VERSION 5.7 ;
  NOWIREEXTENSIONATPIN ON ;
  DIVIDERCHAR "/" ;
  BUSBITCHARS "[]" ;
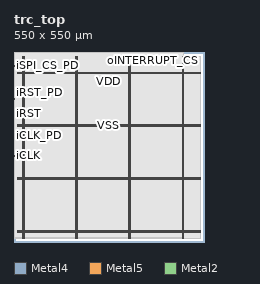
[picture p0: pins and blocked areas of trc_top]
MACRO trc_top
  CLASS BLOCK ;
  FOREIGN trc_top ;
  ORIGIN 0.000 0.000 ;
  SIZE 550.000 BY 550.000 ;
  PIN VDD
    DIRECTION INOUT ;
    USE POWER ;
    PORT
      LAYER Metal4 ;
        RECT 25.600 11.460 27.200 537.340 ;
    END
    PORT
      LAYER Metal4 ;
        RECT 179.200 11.460 180.800 537.340 ;
    END
    PORT
      LAYER Metal4 ;
        RECT 332.800 11.460 334.400 537.340 ;
    END
    PORT
      LAYER Metal4 ;
        RECT 486.400 11.460 488.000 537.340 ;
    END
    PORT
      LAYER Metal5 ;
        RECT 10.080 27.610 539.840 29.210 ;
    END
    PORT
      LAYER Metal5 ;
        RECT 10.080 180.790 539.840 182.390 ;
    END
    PORT
      LAYER Metal5 ;
        RECT 10.080 333.970 539.840 335.570 ;
    END
    PORT
      LAYER Metal5 ;
        RECT 10.080 487.150 539.840 488.750 ;
    END
  END VDD
  PIN VSS
    DIRECTION INOUT ;
    USE GROUND ;
    PORT
      LAYER Metal4 ;
        RECT 28.900 11.460 30.500 537.340 ;
    END
    PORT
      LAYER Metal4 ;
        RECT 182.500 11.460 184.100 537.340 ;
    END
    PORT
      LAYER Metal4 ;
        RECT 336.100 11.460 337.700 537.340 ;
    END
    PORT
      LAYER Metal4 ;
        RECT 489.700 11.460 491.300 537.340 ;
    END
    PORT
      LAYER Metal5 ;
        RECT 10.080 30.910 539.840 32.510 ;
    END
    PORT
      LAYER Metal5 ;
        RECT 10.080 184.090 539.840 185.690 ;
    END
    PORT
      LAYER Metal5 ;
        RECT 10.080 337.270 539.840 338.870 ;
    END
    PORT
      LAYER Metal5 ;
        RECT 10.080 490.450 539.840 492.050 ;
    END
  END VSS
  PIN iCLK
    DIRECTION INPUT ;
    USE SIGNAL ;
    ANTENNAGATEAREA 4.738000 ;
    PORT
      LAYER Metal2 ;
        RECT 0.000 248.760 1.000 249.140 ;
    END
  END iCLK
  PIN iCLK_PD
    DIRECTION OUTPUT ;
    USE SIGNAL ;
    ANTENNADIFFAREA 0.536800 ;
    PORT
      LAYER Metal2 ;
        RECT 0.000 309.290 1.000 309.670 ;
    END
  END iCLK_PD
  PIN iCLK_PU
    DIRECTION OUTPUT ;
    USE SIGNAL ;
    ANTENNADIFFAREA 0.360800 ;
    PORT
      LAYER Metal2 ;
        RECT 0.000 313.655 1.000 314.035 ;
    END
  END iCLK_PU
  PIN iRST
    DIRECTION INPUT ;
    USE SIGNAL ;
    ANTENNAGATEAREA 4.408000 ;
    PORT
      LAYER Metal2 ;
        RECT 0.000 348.760 1.000 349.140 ;
    END
  END iRST
  PIN iRST_PD
    DIRECTION OUTPUT ;
    USE SIGNAL ;
    ANTENNADIFFAREA 0.360800 ;
    PORT
      LAYER Metal2 ;
        RECT 0.000 409.290 1.000 409.670 ;
    END
  END iRST_PD
  PIN iRST_PU
    DIRECTION OUTPUT ;
    USE SIGNAL ;
    ANTENNADIFFAREA 0.536800 ;
    PORT
      LAYER Metal2 ;
        RECT 0.000 413.655 1.000 414.035 ;
    END
  END iRST_PU
  PIN iSPI_CS
    DIRECTION INPUT ;
    USE SIGNAL ;
    ANTENNAGATEAREA 0.498500 ;
    PORT
      LAYER Metal2 ;
        RECT 0.000 448.760 1.000 449.140 ;
    END
  END iSPI_CS
  PIN iSPI_CS_PD
    DIRECTION OUTPUT ;
    USE SIGNAL ;
    ANTENNADIFFAREA 0.360800 ;
    PORT
      LAYER Metal2 ;
        RECT 0.000 509.290 1.000 509.670 ;
    END
  END iSPI_CS_PD
  PIN iSPI_CS_PU
    DIRECTION OUTPUT ;
    USE SIGNAL ;
    ANTENNADIFFAREA 0.536800 ;
    PORT
      LAYER Metal2 ;
        RECT 0.000 513.655 1.000 514.035 ;
    END
  END iSPI_CS_PU
  PIN iSPI_MOSI
    DIRECTION INPUT ;
    USE SIGNAL ;
    ANTENNAGATEAREA 0.396000 ;
    PORT
      LAYER Metal2 ;
        RECT 133.760 549.000 134.140 550.000 ;
    END
  END iSPI_MOSI
  PIN iSPI_MOSI_PD
    DIRECTION OUTPUT ;
    USE SIGNAL ;
    ANTENNADIFFAREA 0.536800 ;
    PORT
      LAYER Metal2 ;
        RECT 194.290 549.000 194.670 550.000 ;
    END
  END iSPI_MOSI_PD
  PIN iSPI_MOSI_PU
    DIRECTION OUTPUT ;
    USE SIGNAL ;
    ANTENNADIFFAREA 0.360800 ;
    PORT
      LAYER Metal2 ;
        RECT 198.655 549.000 199.035 550.000 ;
    END
  END iSPI_MOSI_PU
  PIN iSPI_SCK
    DIRECTION INPUT ;
    USE SIGNAL ;
    ANTENNAGATEAREA 0.498500 ;
    PORT
      LAYER Metal2 ;
        RECT 33.760 549.000 34.140 550.000 ;
    END
  END iSPI_SCK
  PIN iSPI_SCK_PD
    DIRECTION OUTPUT ;
    USE SIGNAL ;
    ANTENNADIFFAREA 0.536800 ;
    PORT
      LAYER Metal2 ;
        RECT 94.290 549.000 94.670 550.000 ;
    END
  END iSPI_SCK_PD
  PIN iSPI_SCK_PU
    DIRECTION OUTPUT ;
    USE SIGNAL ;
    ANTENNADIFFAREA 0.360800 ;
    PORT
      LAYER Metal2 ;
        RECT 98.655 549.000 99.035 550.000 ;
    END
  END iSPI_SCK_PU
  PIN oINTERRUPT_CS
    DIRECTION OUTPUT ;
    USE SIGNAL ;
    ANTENNADIFFAREA 0.360800 ;
    PORT
      LAYER Metal2 ;
        RECT 401.260 549.000 401.640 550.000 ;
    END
  END oINTERRUPT_CS
  PIN oINTERRUPT_IE
    DIRECTION OUTPUT ;
    USE SIGNAL ;
    ANTENNADIFFAREA 0.360800 ;
    PORT
      LAYER Metal2 ;
        RECT 393.235 549.000 393.615 550.000 ;
    END
  END oINTERRUPT_IE
  PIN oINTERRUPT_IN
    DIRECTION INPUT ;
    USE SIGNAL ;
    PORT
      LAYER Metal2 ;
        RECT 333.760 549.000 334.140 550.000 ;
    END
  END oINTERRUPT_IN
  PIN oINTERRUPT_OE
    DIRECTION OUTPUT ;
    USE SIGNAL ;
    ANTENNADIFFAREA 0.536800 ;
    PORT
      LAYER Metal2 ;
        RECT 334.490 549.000 334.870 550.000 ;
    END
  END oINTERRUPT_OE
  PIN oINTERRUPT_OUT
    DIRECTION OUTPUT ;
    USE SIGNAL ;
    ANTENNADIFFAREA 1.986000 ;
    PORT
      LAYER Metal2 ;
        RECT 335.220 549.000 335.600 550.000 ;
    END
  END oINTERRUPT_OUT
  PIN oINTERRUPT_PD
    DIRECTION OUTPUT ;
    USE SIGNAL ;
    ANTENNADIFFAREA 0.360800 ;
    PORT
      LAYER Metal2 ;
        RECT 394.290 549.000 394.670 550.000 ;
    END
  END oINTERRUPT_PD
  PIN oINTERRUPT_PDRV0
    DIRECTION OUTPUT ;
    USE SIGNAL ;
    ANTENNADIFFAREA 0.536800 ;
    PORT
      LAYER Metal2 ;
        RECT 397.510 549.000 397.890 550.000 ;
    END
  END oINTERRUPT_PDRV0
  PIN oINTERRUPT_PDRV1
    DIRECTION OUTPUT ;
    USE SIGNAL ;
    ANTENNADIFFAREA 0.536800 ;
    PORT
      LAYER Metal2 ;
        RECT 396.800 549.000 397.180 550.000 ;
    END
  END oINTERRUPT_PDRV1
  PIN oINTERRUPT_PU
    DIRECTION OUTPUT ;
    USE SIGNAL ;
    ANTENNADIFFAREA 0.360800 ;
    PORT
      LAYER Metal2 ;
        RECT 398.655 549.000 399.035 550.000 ;
    END
  END oINTERRUPT_PU
  PIN oINTERRUPT_SL
    DIRECTION OUTPUT ;
    USE SIGNAL ;
    ANTENNADIFFAREA 0.360800 ;
    PORT
      LAYER Metal2 ;
        RECT 335.950 549.000 336.330 550.000 ;
    END
  END oINTERRUPT_SL
  PIN oSPI_MISO_CS
    DIRECTION OUTPUT ;
    USE SIGNAL ;
    ANTENNADIFFAREA 0.360800 ;
    PORT
      LAYER Metal2 ;
        RECT 301.260 549.000 301.640 550.000 ;
    END
  END oSPI_MISO_CS
  PIN oSPI_MISO_IE
    DIRECTION OUTPUT ;
    USE SIGNAL ;
    ANTENNADIFFAREA 0.360800 ;
    PORT
      LAYER Metal2 ;
        RECT 293.235 549.000 293.615 550.000 ;
    END
  END oSPI_MISO_IE
  PIN oSPI_MISO_IN
    DIRECTION INPUT ;
    USE SIGNAL ;
    PORT
      LAYER Metal2 ;
        RECT 233.760 549.000 234.140 550.000 ;
    END
  END oSPI_MISO_IN
  PIN oSPI_MISO_OE
    DIRECTION OUTPUT ;
    USE SIGNAL ;
    ANTENNADIFFAREA 0.536800 ;
    PORT
      LAYER Metal2 ;
        RECT 234.490 549.000 234.870 550.000 ;
    END
  END oSPI_MISO_OE
  PIN oSPI_MISO_OUT
    DIRECTION OUTPUT ;
    USE SIGNAL ;
    ANTENNADIFFAREA 1.986000 ;
    PORT
      LAYER Metal2 ;
        RECT 235.220 549.000 235.600 550.000 ;
    END
  END oSPI_MISO_OUT
  PIN oSPI_MISO_PD
    DIRECTION OUTPUT ;
    USE SIGNAL ;
    ANTENNADIFFAREA 0.360800 ;
    PORT
      LAYER Metal2 ;
        RECT 294.290 549.000 294.670 550.000 ;
    END
  END oSPI_MISO_PD
  PIN oSPI_MISO_PDRV0
    DIRECTION OUTPUT ;
    USE SIGNAL ;
    ANTENNADIFFAREA 0.536800 ;
    PORT
      LAYER Metal2 ;
        RECT 297.510 549.000 297.890 550.000 ;
    END
  END oSPI_MISO_PDRV0
  PIN oSPI_MISO_PDRV1
    DIRECTION OUTPUT ;
    USE SIGNAL ;
    ANTENNADIFFAREA 0.536800 ;
    PORT
      LAYER Metal2 ;
        RECT 296.800 549.000 297.180 550.000 ;
    END
  END oSPI_MISO_PDRV1
  PIN oSPI_MISO_PU
    DIRECTION OUTPUT ;
    USE SIGNAL ;
    ANTENNADIFFAREA 0.360800 ;
    PORT
      LAYER Metal2 ;
        RECT 298.655 549.000 299.035 550.000 ;
    END
  END oSPI_MISO_PU
  PIN oSPI_MISO_SL
    DIRECTION OUTPUT ;
    USE SIGNAL ;
    ANTENNADIFFAREA 0.360800 ;
    PORT
      LAYER Metal2 ;
        RECT 235.950 549.000 236.330 550.000 ;
    END
  END oSPI_MISO_SL
  OBS
      LAYER Nwell ;
        RECT 9.650 11.330 540.270 537.470 ;
      LAYER Metal1 ;
        RECT 10.080 11.460 539.840 537.340 ;
      LAYER Metal2 ;
        RECT 0.140 548.700 33.460 549.220 ;
        RECT 34.440 548.700 93.990 549.220 ;
        RECT 94.970 548.700 98.355 549.220 ;
        RECT 99.335 548.700 133.460 549.220 ;
        RECT 134.440 548.700 193.990 549.220 ;
        RECT 194.970 548.700 198.355 549.220 ;
        RECT 199.335 548.700 233.460 549.220 ;
        RECT 236.630 548.700 292.935 549.220 ;
        RECT 293.915 548.700 293.990 549.220 ;
        RECT 294.970 548.700 296.500 549.220 ;
        RECT 298.190 548.700 298.355 549.220 ;
        RECT 299.335 548.700 300.960 549.220 ;
        RECT 301.940 548.700 333.460 549.220 ;
        RECT 336.630 548.700 392.935 549.220 ;
        RECT 393.915 548.700 393.990 549.220 ;
        RECT 394.970 548.700 396.500 549.220 ;
        RECT 398.190 548.700 398.355 549.220 ;
        RECT 399.335 548.700 400.960 549.220 ;
        RECT 401.940 548.700 491.160 549.220 ;
        RECT 0.140 514.335 491.160 548.700 ;
        RECT 1.300 513.355 491.160 514.335 ;
        RECT 0.140 509.970 491.160 513.355 ;
        RECT 1.300 508.990 491.160 509.970 ;
        RECT 0.140 449.440 491.160 508.990 ;
        RECT 1.300 448.460 491.160 449.440 ;
        RECT 0.140 414.335 491.160 448.460 ;
        RECT 1.300 413.355 491.160 414.335 ;
        RECT 0.140 409.970 491.160 413.355 ;
        RECT 1.300 408.990 491.160 409.970 ;
        RECT 0.140 349.440 491.160 408.990 ;
        RECT 1.300 348.460 491.160 349.440 ;
        RECT 0.140 314.335 491.160 348.460 ;
        RECT 1.300 313.355 491.160 314.335 ;
        RECT 0.140 309.970 491.160 313.355 ;
        RECT 1.300 308.990 491.160 309.970 ;
        RECT 0.140 249.440 491.160 308.990 ;
        RECT 1.300 248.460 491.160 249.440 ;
        RECT 0.140 11.570 491.160 248.460 ;
      LAYER Metal3 ;
        RECT 0.650 11.620 491.210 547.540 ;
  END
END trc_top
END LIBRARY

